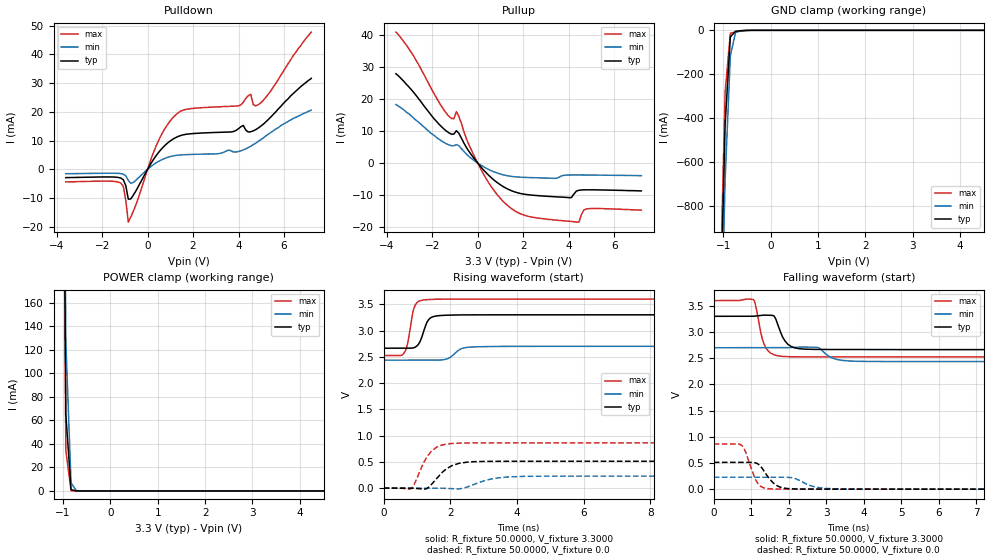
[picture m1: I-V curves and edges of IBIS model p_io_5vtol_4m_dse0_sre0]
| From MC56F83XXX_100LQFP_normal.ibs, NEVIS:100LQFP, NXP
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[Model] p_io_5vtol_4m_dse0_sre0
|   Model p_io_5vtol_4m_dse0_sre0
| Library cells for typ/min/max conditions are connected as defined below:
|  pad - External Pad
|  ipp_do - Core Input
|  ipp_obe - Output Buffer Enable
|  esd_boost - vdd_s_3v
|  esd_bus - vdd_s_3v
|  ipp_ame - vss_s_lv
|  ipp_dse - vss_s_lv
|  ipp_ina40a_5vtol - NC
|  ipp_ina40b_5vtol - NC
|  ipp_ina_5vtol - NC
|  ipp_ina_mux_3v - NC
|  ipp_ind - NC
|  ipp_ind_3v - NC
|  ipp_pue - vss_s_lv
|  ipp_sre - vss_s_lv
|  tie_3v - vdd_s_3v
|  tie_hi - vdd_s_lv
|  vbuf_3v - vdd_s_3v
|  vdd_bulk_lv - vdd_s_lv
|  vdd_s_3v - vdd_s_3v
|  vdd_s_lv - vdd_s_lv
|  vss_bulk - vss_s_3v
|  vss_s_3v - vss_s_3v
|  vss_s_lv - vss_s_lv
| All other pins connected to ground
Model_type I/O
Polarity   Non-Inverting
Enable   Active-High
Vinl =   1.1550V
Vinh =   2.3100V
Vmeas =  1.6500V
Cref =   25.0000pF
Rref =   0.5000k
Vref =   0.0V
C_comp   2.7442pF   2.6088pF   2.9166pF
[Temperature Range]   25.0000   0.1250k   -40.0000
[Voltage Range]   3.3000V   2.7000V   3.6000V
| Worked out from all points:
|   slope of the pulldown table from 0 to 0.495 V, typ, clamps not added: 82.8 ohm
|   slope of the pullup table from 0 to 0.495 V, typ, clamps not added: 127 ohm
|   GND clamp passes 1 mA (typ) near -0.56 V on its own axis
|   POWER clamp passes 1 mA (typ) near -0.82 V on its own axis
|   rising waveform, R_fixture 50.0000, V_fixture 3.3000: 20-80 % time 220ps typ, 318ps min, 177ps max; typ from 2.66 V to 3.3 V
|   rising waveform, R_fixture 50.0000, V_fixture 0.0: 20-80 % time 520ps typ, 708ps min, 427ps max; typ from 0 V to 0.512 V
|   falling waveform, R_fixture 50.0000, V_fixture 3.3000: 20-80 % time 253ps typ, 333ps min, 210ps max; typ from 3.3 V to 2.66 V
|   falling waveform, R_fixture 50.0000, V_fixture 0.0: 20-80 % time 337ps typ, 455ps min, 264ps max; typ from 0.512 V to 0 V
[Pulldown]
|Voltage   I(typ)   I(min)   I(max)
-3.6V     -2.92mA    -1.56mA    -4.41mA
-1.18V    -3.075mA   -1.514mA   -4.85mA
-1.07V    -3.642mA   -1.711mA   -5.917mA
-850mV    -10.41mA   -3.881mA   -18.45mA
360mV     4.579mA    2.156mA    7.833mA
1.13V     10.56mA    4.658mA    18.11mA
1.79V     12.28mA    5.123mA    21mA
3.99V     14.08mA    6.16mA     22.06mA
4.54V     13.07mA    8.03mA     26.11mA
4.65V     13.38mA    8.6mA      22.52mA
4.87V     14.37mA    9.7mA      22.49mA
7.2V      31.7mA     20.6mA     47.8mA
[Pullup]
|Voltage   I(typ)   I(min)   I(max)
-3.6V     27.9mA     18.3mA     40.9mA
-2.81V    22mA       14mA       33.3mA
-1.38V    10.01mA    6.04mA     15.54mA
-1.05V    9.045mA    5.403mA    13.85mA
-940mV    10.12mA    5.768mA    16.08mA
-390mV    3.678mA    2.088mA    5.744mA
270mV     -2.258mA   -1.197mA   -3.638mA
1.48V     -8.613mA   -4.152mA   -14.19mA
4.01V     -10.78mA   -3.728mA   -18.16mA
4.45V     -8.487mA   -3.709mA   -18.45mA
4.78V     -8.342mA   -3.73mA    -14.33mA
7.2V      -8.69mA    -3.91mA    -14.69mA
[GND_clamp]
|Voltage   I(typ)   I(min)   I(max)
-3.6V     -31.15A    -31.13A    -31.21A
-1.07V    -1.387A    -1.641A    -1.238A
-960mV    -429.3mA   -680.2mA   -281.1mA
-850mV    -29.75mA   -116.1mA   -13.24mA
-740mV    -4.234mA   -9.703mA   -7.092mA
-630mV    -1.925mA   -1.63mA    -3.569mA
-410mV    -31.96uA   -64.36uA   -35uA
7.2V      0A         0A         0A
[POWER_clamp]
|Voltage   I(typ)   I(min)   I(max)
-3.6V     31.35A     31.03A     31.61A
-1.05V    682.2mA    740.4mA    662.9mA
-940mV    65.1mA     126.6mA    34.32mA
-830mV    1.105mA    6.829mA    165.4uA
-720mV    15.33uA    281.3uA    694.4nA
-610mV    212.1nA    11.41uA    2.964nA
7.2V      0A         0A         0A
[Ramp]
| variable   typ   min   max
dV/dt_r  0.3070/0.5203n   0.1368/0.7078n   0.5174/0.4265n
dV/dt_f  0.3816/0.2526n   0.1581/0.3329n   0.6454/0.2102n
R_load = 50.0000
[Rising Waveform]
R_fixture= 50.0000
V_fixture= 3.3000
V_fixture_min= 2.7000
V_fixture_max= 3.6000
|time   V(typ)   V(min)   V(max)
0s        2.664V     2.436V     2.524V
610.3ps   2.664V     2.436V     2.569V
714.5ps   2.664V     2.436V     2.741V
910.9ps   2.675V     2.436V     3.431V
1.094ns   2.792V     2.437V     3.568V
1.273ns   3.119V     2.437V     3.588V
1.552ns   3.276V     2.437V     3.596V
2.35ns    3.298V     2.659V     3.599V
2.979ns   3.3V       2.694V     3.599V
20ns      3.3V       2.7V       3.6V
[Rising Waveform]
R_fixture= 50.0000
V_fixture= 0.0
V_fixture_min= 0.0
V_fixture_max= 0.0
|time   V(typ)   V(min)   V(max)
0s        1.096nV    96.66nV    914.3pV
817.3ps   -174.2uV   1.791uV    -11.85mV
1.238ns   -20.09mV   132uV      527.3mV
1.432ns   68.46mV    364.3uV    703.1mV
1.774ns   310.6mV    -2.683mV   823mV
2.042ns   424.3mV    -10.1mV    850.1mV
2.694ns   503.4mV    66.34mV    860.8mV
3.192ns   509.9mV    168.5mV    861.5mV
4.049ns   511.3mV    221.6mV    861.7mV
20ns      511.7mV    228.1mV    862.3mV
[Falling Waveform]
R_fixture= 50.0000
V_fixture= 3.3000
V_fixture_min= 2.7000
V_fixture_max= 3.6000
|time   V(typ)   V(min)   V(max)
0s        3.3V       2.7V       3.6V
1.056ns   3.301V     2.7V       3.62V
1.285ns   3.321V     2.7V       2.894V
1.39ns    3.322V     2.7V       2.695V
1.614ns   3.301V     2.7V       2.565V
1.898ns   2.83V      2.7V       2.531V
2.744ns   2.668V     2.71V      2.525V
3.178ns   2.667V     2.499V     2.525V
3.812ns   2.665V     2.441V     2.525V
20ns      2.664V     2.436V     2.524V
[Falling Waveform]
R_fixture= 50.0000
V_fixture= 0.0
V_fixture_min= 0.0
V_fixture_max= 0.0
|time   V(typ)   V(min)   V(max)
0s        511.8mV    228.1mV    862.4mV
740.7ps   511.8mV    228.1mV    838mV
824.6ps   511.7mV    228.1mV    750.7mV
1.166ns   486.7mV    228.1mV    119mV
1.481ns   202.1mV    228.1mV    6.302mV
1.652ns   81.2mV     228mV      2.01mV
1.911ns   16.02mV    227.7mV    767.9uV
2.752ns   448uV      36.41mV    432.9uV
3.473ns   288.4uV    2.353mV    359uV
20ns      60.38uV    38.43uV    87.29uV
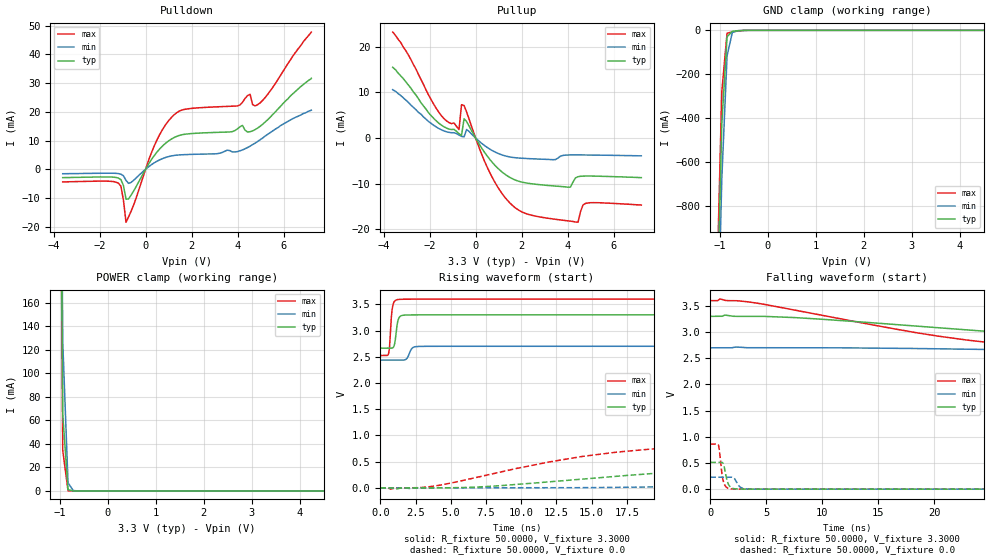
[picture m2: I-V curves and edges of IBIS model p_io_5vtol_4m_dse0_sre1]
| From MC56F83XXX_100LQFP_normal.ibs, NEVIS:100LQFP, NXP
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[Model] p_io_5vtol_4m_dse0_sre1
|   Model p_io_5vtol_4m_dse0_sre1
| Library cells for typ/min/max conditions are connected as defined below:
|  pad - External Pad
|  ipp_do - Core Input
|  ipp_obe - Output Buffer Enable
|  esd_boost - vdd_s_3v
|  esd_bus - vdd_s_3v
|  ipp_ame - vss_s_lv
|  ipp_dse - vss_s_lv
|  ipp_ina40a_5vtol - NC
|  ipp_ina40b_5vtol - NC
|  ipp_ina_5vtol - NC
|  ipp_ina_mux_3v - NC
|  ipp_ind - NC
|  ipp_ind_3v - NC
|  ipp_pue - vss_s_lv
|  ipp_sre - vdd_s_lv
|  tie_3v - vdd_s_3v
|  tie_hi - vdd_s_lv
|  vbuf_3v - vdd_s_3v
|  vdd_bulk_lv - vdd_s_lv
|  vdd_s_3v - vdd_s_3v
|  vdd_s_lv - vdd_s_lv
|  vss_bulk - vss_s_3v
|  vss_s_3v - vss_s_3v
|  vss_s_lv - vss_s_lv
| All other pins connected to ground
Model_type I/O
Polarity   Non-Inverting
Enable   Active-High
Vinl =   1.1550V
Vinh =   2.3100V
Vmeas =  1.6500V
Cref =   25.0000pF
Rref =   0.5000k
Vref =   0.0V
C_comp   2.7442pF   2.6088pF   2.9166pF
[Temperature Range]   25.0000   0.1250k   -40.0000
[Voltage Range]   3.3000V   2.7000V   3.6000V
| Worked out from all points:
|   slope of the pulldown table from 0 to 0.495 V, typ, clamps not added: 82.8 ohm
|   slope of the pullup table from 0 to 0.495 V, typ, clamps not added: 127 ohm
|   GND clamp passes 1 mA (typ) near -0.56 V on its own axis
|   POWER clamp passes 1 mA (typ) near -0.82 V on its own axis
|   rising waveform, R_fixture 50.0000, V_fixture 3.3000: 20-80 % time 192ps typ, 268ps min, 163ps max; typ from 2.66 V to 3.3 V
|   rising waveform, R_fixture 50.0000, V_fixture 0.0: 20-80 % time 17.3ns typ, 32.4ns min, 10.8ns max; typ from 0 V to 0.512 V
|   falling waveform, R_fixture 50.0000, V_fixture 3.3000: 20-80 % time 29.9ns typ, 51ns min, 19.5ns max; typ from 3.3 V to 2.66 V
|   falling waveform, R_fixture 50.0000, V_fixture 0.0: 20-80 % time 342ps typ, 422ps min, 300ps max; typ from 0.512 V to 0 V
[Pulldown]
|Voltage   I(typ)   I(min)   I(max)
-3.6V     -2.92mA    -1.56mA    -4.41mA
-1.18V    -3.075mA   -1.514mA   -4.85mA
-1.07V    -3.642mA   -1.711mA   -5.917mA
-850mV    -10.41mA   -3.881mA   -18.45mA
360mV     4.579mA    2.156mA    7.833mA
1.13V     10.56mA    4.658mA    18.11mA
1.79V     12.28mA    5.123mA    21mA
3.99V     14.08mA    6.16mA     22.06mA
4.54V     13.07mA    8.03mA     26.11mA
4.65V     13.38mA    8.6mA      22.52mA
4.87V     14.37mA    9.7mA      22.49mA
7.2V      31.7mA     20.6mA     47.8mA
[Pullup]
|Voltage   I(typ)   I(min)   I(max)
-3.6V     15.5mA     10.6mA     23.2mA
-1.38V    2.47mA     1.56mA     4.28mA
-720mV    935.3uA    641.5uA    1.84mA
-610mV    580.7uA    348.6uA    7.293mA
-500mV    4.215mA    257.3uA    7.125mA
-390mV    3.605mA    1.85mA     5.718mA
710mV     -5.257mA   -2.715mA   -8.512mA
1.81V     -9.375mA   -4.366mA   -15.61mA
4.12V     -10.77mA   -3.714mA   -18.22mA
4.45V     -8.487mA   -3.709mA   -18.45mA
4.78V     -8.342mA   -3.73mA    -14.33mA
7.2V      -8.69mA    -3.91mA    -14.69mA
[GND_clamp]
|Voltage   I(typ)   I(min)   I(max)
-3.6V     -31.15A    -31.13A    -31.21A
-1.07V    -1.387A    -1.641A    -1.238A
-960mV    -429.3mA   -680.2mA   -281.1mA
-850mV    -29.75mA   -116.1mA   -13.24mA
-740mV    -4.234mA   -9.703mA   -7.092mA
-630mV    -1.925mA   -1.63mA    -3.569mA
-410mV    -31.96uA   -64.36uA   -35uA
7.2V      0A         0A         0A
[POWER_clamp]
|Voltage   I(typ)   I(min)   I(max)
-3.6V     31.35A     31.03A     31.61A
-1.05V    682.2mA    740.4mA    662.9mA
-940mV    65.1mA     126.6mA    34.32mA
-830mV    1.105mA    6.829mA    165.4uA
-720mV    15.33uA    281.3uA    694.4nA
-610mV    212.1nA    11.41uA    2.964nA
7.2V      0A         0A         0A
[Ramp]
| variable   typ   min   max
dV/dt_r  0.3071/17.2926n   0.1369/32.3674n   0.5175/10.7611n
dV/dt_f  0.3817/29.8719n   0.1576/51.0200n   0.6456/19.5314n
R_load = 50.0000
[Rising Waveform]
R_fixture= 50.0000
V_fixture= 3.3000
V_fixture_min= 2.7000
V_fixture_max= 3.6000
|time   V(typ)   V(min)   V(max)
0s        2.664V     2.437V     2.524V
605.3ps   2.664V     2.437V     2.579V
657.9ps   2.664V     2.437V     2.693V
807.7ps   2.664V     2.437V     3.325V
923.6ps   2.679V     2.436V     3.511V
1.276ns   3.209V     2.437V     3.592V
1.646ns   3.293V     2.437V     3.597V
2.341ns   3.298V     2.679V     3.598V
3.739ns   3.299V     2.699V     3.598V
250ns     3.3V       2.7V       3.6V
[Rising Waveform]
R_fixture= 50.0000
V_fixture= 0.0
V_fixture_min= 0.0
V_fixture_max= 0.0
|time   V(typ)   V(min)   V(max)
0s        1.096nV    96.66nV    914.3pV
730.2ps   540.1uV    1.417uV    -25.29mV
3.533ns   -267.8uV   -118.1uV   22.43mV
11.84ns   111.3mV    1.042mV    487mV
16.8ns    222mV      9.094mV    681.3mV
24.08ns   354mV      38.46mV    807.6mV
31.02ns   430.3mV    75.05mV    845.8mV
49.75ns   501.2mV    160.4mV    861.8mV
86.96ns   511.7mV    219.4mV    862.5mV
250ns     511.8mV    228.1mV    862.5mV
[Falling Waveform]
R_fixture= 50.0000
V_fixture= 3.3000
V_fixture_min= 2.7000
V_fixture_max= 3.6000
|time   V(typ)   V(min)   V(max)
0s        3.3V       2.7V       3.6V
896.8ps   3.3V       2.7V       3.63V
3.769ns   3.3V       2.7V       3.565V
18.49ns   3.112V     2.686V     2.984V
25.66ns   2.998V     2.664V     2.78V
33.75ns   2.887V     2.635V     2.66V
43.81ns   2.796V     2.595V     2.594V
65.21ns   2.714V     2.521V     2.543V
96.83ns   2.677V     2.472V     2.527V
250ns     2.664V     2.437V     2.524V
[Falling Waveform]
R_fixture= 50.0000
V_fixture= 0.0
V_fixture_min= 0.0
V_fixture_max= 0.0
|time   V(typ)   V(min)   V(max)
0s        511.8mV    228.1mV    862.4mV
711.3ps   511.8mV    228.1mV    851.3mV
813.8ps   511.8mV    228.1mV    743.1mV
1.045ns   511.3mV    228.1mV    281.6mV
1.18ns    474mV      228.1mV    137.9mV
1.57ns    116.7mV    228mV      19.01mV
2.147ns   7.963mV    204.4mV    2.261mV
2.747ns   1.249mV    29.86mV    1.357mV
3.983ns   641.3uV    486.1uV    1mV
250ns     26.94nV    927.1nV    8.795nV
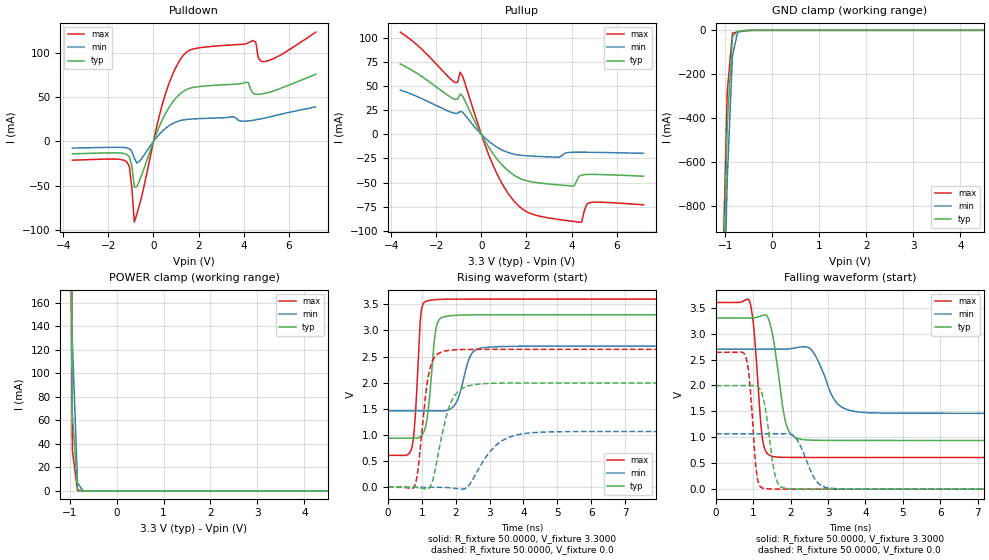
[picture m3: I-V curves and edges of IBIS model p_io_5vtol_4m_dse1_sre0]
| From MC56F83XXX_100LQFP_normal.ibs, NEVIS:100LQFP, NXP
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[Model] p_io_5vtol_4m_dse1_sre0
|   Model p_io_5vtol_4m_dse1_sre0
| Library cells for typ/min/max conditions are connected as defined below:
|  pad - External Pad
|  ipp_do - Core Input
|  ipp_obe - Output Buffer Enable
|  esd_boost - vdd_s_3v
|  esd_bus - vdd_s_3v
|  ipp_ame - vss_s_lv
|  ipp_dse - vdd_s_lv
|  ipp_ina40a_5vtol - NC
|  ipp_ina40b_5vtol - NC
|  ipp_ina_5vtol - NC
|  ipp_ina_mux_3v - NC
|  ipp_ind - NC
|  ipp_ind_3v - NC
|  ipp_pue - vss_s_lv
|  ipp_sre - vss_s_lv
|  tie_3v - vdd_s_3v
|  tie_hi - vdd_s_lv
|  vbuf_3v - vdd_s_3v
|  vdd_bulk_lv - vdd_s_lv
|  vdd_s_3v - vdd_s_3v
|  vdd_s_lv - vdd_s_lv
|  vss_bulk - vss_s_3v
|  vss_s_3v - vss_s_3v
|  vss_s_lv - vss_s_lv
| All other pins connected to ground
Model_type I/O
Polarity   Non-Inverting
Enable   Active-High
Vinl =   1.1550V
Vinh =   2.3100V
Vmeas =  1.6500V
Cref =   25.0000pF
Rref =   0.5000k
Vref =   0.0V
C_comp   2.7442pF   2.6088pF   2.9166pF
[Temperature Range]   25.0000   0.1250k   -40.0000
[Voltage Range]   3.3000V   2.7000V   3.6000V
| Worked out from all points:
|   slope of the pulldown table from 0 to 0.495 V, typ, clamps not added: 16.7 ohm
|   slope of the pullup table from 0 to 0.495 V, typ, clamps not added: 25.7 ohm
|   GND clamp passes 1 mA (typ) near -0.56 V on its own axis
|   POWER clamp passes 1 mA (typ) near -0.82 V on its own axis
|   rising waveform, R_fixture 50.0000, V_fixture 3.3000: 20-80 % time 198ps typ, 316ps min, 148ps max; typ from 0.938 V to 3.3 V
|   rising waveform, R_fixture 50.0000, V_fixture 0.0: 20-80 % time 433ps typ, 731ps min, 266ps max; typ from 0 V to 2 V
|   falling waveform, R_fixture 50.0000, V_fixture 3.3000: 20-80 % time 273ps typ, 438ps min, 181ps max; typ from 3.3 V to 0.939 V
|   falling waveform, R_fixture 50.0000, V_fixture 0.0: 20-80 % time 233ps typ, 387ps min, 161ps max; typ from 2 V to 0 V
[Pulldown]
|Voltage   I(typ)   I(min)   I(max)
-3.6V     -13.95mA   -7.44mA    -21.1mA
-1.18V    -14.7mA    -7.219mA   -23.24mA
-1.07V    -17.36mA   -8.141mA   -28.3mA
-850mV    -51.45mA   -18.95mA   -91.09mA
-630mV    -44.71mA   -22.71mA   -72.44mA
470mV     28.45mA    13.31mA    48.59mA
1.35V     56.89mA    24.4mA     97.86mA
4.1V      66.73mA    22.95mA    110.2mA
4.43V     54.09mA    23.92mA    113.9mA
4.65V     53.15mA    25mA       94.51mA
4.98V     54.48mA    26.7mA     90.35mA
7.2V      75.8mA     39.1mA     123.4mA
[Pullup]
|Voltage   I(typ)   I(min)   I(max)
-3.6V     72.9mA     45.9mA     106mA
-1.16V    36.23mA    21.7mA     53.64mA
-1.05V    36.74mA    21.9mA     54.26mA
-940mV    41.85mA    23.77mA    64.43mA
600mV     -22.66mA   -11.88mA   -36.28mA
1.15V     -36.98mA   -18.56mA   -59.89mA
1.81V     -46.62mA   -21.82mA   -77.16mA
4.12V     -53.36mA   -18.54mA   -90.34mA
4.45V     -42.19mA   -18.52mA   -91.04mA
4.67V     -41.57mA   -18.57mA   -72.57mA
4.78V     -41.5mA    -18.6mA    -70.99mA
7.2V      -43.39mA   -19.66mA   -73.06mA
[GND_clamp]
|Voltage   I(typ)   I(min)   I(max)
-3.6V     -31.15A    -31.13A    -31.21A
-1.07V    -1.387A    -1.641A    -1.238A
-960mV    -429.3mA   -680.2mA   -281.1mA
-850mV    -29.75mA   -116.1mA   -13.24mA
-740mV    -4.234mA   -9.703mA   -7.092mA
-630mV    -1.925mA   -1.63mA    -3.569mA
-410mV    -31.96uA   -64.36uA   -35uA
7.2V      0A         0A         0A
[POWER_clamp]
|Voltage   I(typ)   I(min)   I(max)
-3.6V     31.35A     31.03A     31.61A
-1.05V    682.2mA    740.4mA    662.9mA
-940mV    65.1mA     126.6mA    34.32mA
-830mV    1.105mA    6.829mA    165.4uA
-720mV    15.33uA    281.3uA    694.4nA
-610mV    212.1nA    11.41uA    2.964nA
7.2V      0A         0A         0A
[Ramp]
| variable   typ   min   max
dV/dt_r  1.1975/0.4329n   0.6401/0.7312n   1.5830/0.2663n
dV/dt_f  1.4166/0.2733n   0.7428/0.4382n   1.7935/0.1810n
R_load = 50.0000
[Rising Waveform]
R_fixture= 50.0000
V_fixture= 3.3000
V_fixture_min= 2.7000
V_fixture_max= 3.6000
|time   V(typ)   V(min)   V(max)
0s        938.5mV    1.461V     610.4mV
700.1ps   938.2mV    1.461V     747.1mV
796.4ps   936.7mV    1.461V     1.287V
950.6ps   966.3mV    1.461V     3.178V
1.101ns   1.142V     1.462V     3.551V
1.388ns   2.926V     1.461V     3.588V
1.622ns   3.255V     1.459V     3.595V
1.984ns   3.288V     1.584V     3.598V
2.713ns   3.298V     2.658V     3.599V
10ns      3.3V       2.7V       3.6V
[Rising Waveform]
R_fixture= 50.0000
V_fixture= 0.0
V_fixture_min= 0.0
V_fixture_max= 0.0
|time   V(typ)   V(min)   V(max)
0s        411.9pV    47.82nV    286.1pV
789.5ps   -503.9uV   655.3nV    31.27mV
878.5ps   -6.744mV   -6.775uV   304.7mV
1.188ns   -27.08mV   110.8uV    2.128V
1.538ns   828.6mV    -14.89uV   2.576V
1.891ns   1.669V     -15.27mV   2.625V
2.523ns   1.961V     173.5mV    2.637V
3.139ns   1.99V      774.3mV    2.638V
3.956ns   1.995V     1.021V     2.638V
10ns      1.996V     1.067V     2.638V
[Falling Waveform]
R_fixture= 50.0000
V_fixture= 3.3000
V_fixture_min= 2.7000
V_fixture_max= 3.6000
|time   V(typ)   V(min)   V(max)
0s        3.3V       2.7V       3.6V
897ps     3.3V       2.7V       3.62V
1.012ns   3.302V     2.7V       3.118V
1.248ns   3.352V     2.7V       952.4mV
1.481ns   3.092V     2.7V       637.9mV
1.861ns   1.291V     2.7V       613mV
2.204ns   973.7mV    2.735V     611.7mV
2.551ns   944.9mV    2.689V     611.3mV
3.583ns   939.7mV    1.518V     611mV
10ns      939mV      1.462V     610.8mV
[Falling Waveform]
R_fixture= 50.0000
V_fixture= 0.0
V_fixture_min= 0.0
V_fixture_max= 0.0
|time   V(typ)   V(min)   V(max)
0s        1.996V     1.067V     2.639V
793.2ps   1.996V     1.067V     2.557V
892.4ps   1.996V     1.067V     2.131V
1.088ns   1.992V     1.067V     303.9mV
1.245ns   1.808V     1.067V     21.49mV
1.576ns   285.6mV    1.067V     1.916mV
1.813ns   22.93mV    1.069V     779.9uV
2.113ns   4.177mV    1.006V     534.5uV
2.932ns   535.4uV    34.39mV    380.9uV
10ns      242.2uV    204.3uV    218.8uV
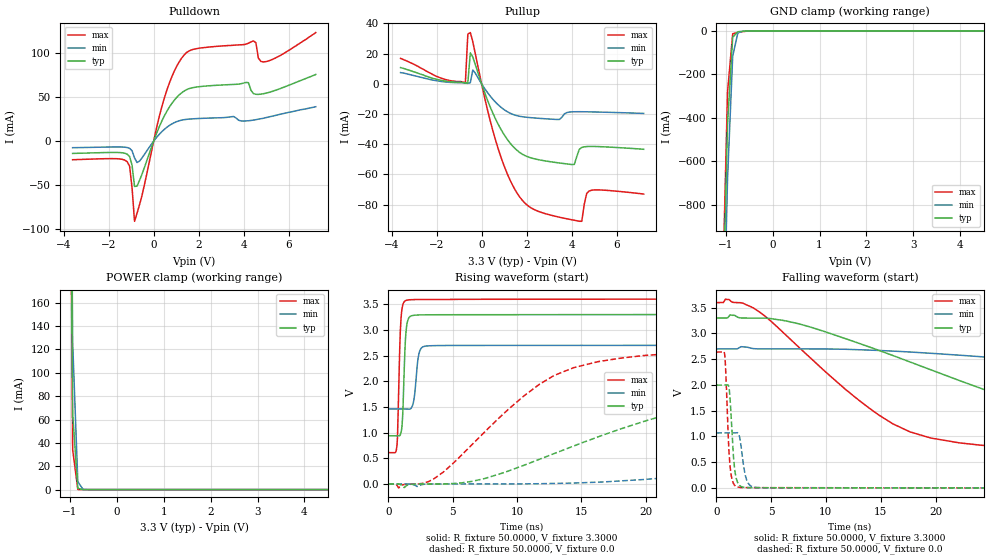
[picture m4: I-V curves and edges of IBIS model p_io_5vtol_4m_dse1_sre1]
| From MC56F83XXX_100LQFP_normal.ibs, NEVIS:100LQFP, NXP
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[Model] p_io_5vtol_4m_dse1_sre1
|   Model p_io_5vtol_4m_dse1_sre1
| Library cells for typ/min/max conditions are connected as defined below:
|  pad - External Pad
|  ipp_do - Core Input
|  ipp_obe - Output Buffer Enable
|  esd_boost - vdd_s_3v
|  esd_bus - vdd_s_3v
|  ipp_ame - vss_s_lv
|  ipp_dse - vdd_s_lv
|  ipp_ina40a_5vtol - NC
|  ipp_ina40b_5vtol - NC
|  ipp_ina_5vtol - NC
|  ipp_ina_mux_3v - NC
|  ipp_ind - NC
|  ipp_ind_3v - NC
|  ipp_pue - vss_s_lv
|  ipp_sre - vdd_s_lv
|  tie_3v - vdd_s_3v
|  tie_hi - vdd_s_lv
|  vbuf_3v - vdd_s_3v
|  vdd_bulk_lv - vdd_s_lv
|  vdd_s_3v - vdd_s_3v
|  vdd_s_lv - vdd_s_lv
|  vss_bulk - vss_s_3v
|  vss_s_3v - vss_s_3v
|  vss_s_lv - vss_s_lv
| All other pins connected to ground
Model_type I/O
Polarity   Non-Inverting
Enable   Active-High
Vinl =   1.1550V
Vinh =   2.3100V
Vmeas =  1.6500V
Cref =   25.0000pF
Rref =   0.5000k
Vref =   0.0V
C_comp   2.7442pF   2.6088pF   2.9166pF
[Temperature Range]   25.0000   0.1250k   -40.0000
[Voltage Range]   3.3000V   2.7000V   3.6000V
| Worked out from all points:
|   slope of the pulldown table from 0 to 0.495 V, typ, clamps not added: 16.7 ohm
|   slope of the pullup table from 0 to 0.495 V, typ, clamps not added: 25.7 ohm
|   GND clamp passes 1 mA (typ) near -0.56 V on its own axis
|   POWER clamp passes 1 mA (typ) near -0.82 V on its own axis
|   rising waveform, R_fixture 50.0000, V_fixture 3.3000: 20-80 % time 204ps typ, 291ps min, 192ps max; typ from 0.938 V to 3.3 V
|   rising waveform, R_fixture 50.0000, V_fixture 0.0: 20-80 % time 15ns typ, 33.8ns min, 7.32ns max; typ from 0 V to 2 V
|   falling waveform, R_fixture 50.0000, V_fixture 3.3000: 20-80 % time 20.3ns typ, 47.8ns min, 10.3ns max; typ from 3.3 V to 0.939 V
|   falling waveform, R_fixture 50.0000, V_fixture 0.0: 20-80 % time 361ps typ, 455ps min, 322ps max; typ from 2 V to 0 V
[Pulldown]
|Voltage   I(typ)   I(min)   I(max)
-3.6V     -13.95mA   -7.44mA    -21.1mA
-1.18V    -14.7mA    -7.219mA   -23.24mA
-1.07V    -17.36mA   -8.141mA   -28.3mA
-850mV    -51.45mA   -18.95mA   -91.09mA
-630mV    -44.71mA   -22.71mA   -72.44mA
470mV     28.45mA    13.31mA    48.59mA
1.35V     56.89mA    24.4mA     97.86mA
4.1V      66.73mA    22.95mA    110.2mA
4.43V     54.09mA    23.92mA    113.9mA
4.65V     53.15mA    25mA       94.51mA
4.98V     54.48mA    26.7mA     90.35mA
7.2V      75.8mA     39.1mA     123.4mA
[Pullup]
|Voltage   I(typ)   I(min)   I(max)
-3.6V     10.7mA     7.4mA      16.8mA
-720mV    464.1uA    412uA      663.7uA
-610mV    644.7uA    224.1uA    32.84mA
-500mV    20.43mA    694.5uA    33.88mA
-390mV    17.73mA    9.113mA    27.82mA
270mV     -11.14mA   -5.959mA   -17.74mA
930mV     -31.96mA   -16.36mA   -51.5mA
2.25V     -49.29mA   -22.53mA   -82.62mA
4.12V     -53.36mA   -18.54mA   -90.34mA
4.45V     -42.19mA   -18.52mA   -91.04mA
4.78V     -41.5mA    -18.6mA    -70.99mA
7.2V      -43.37mA   -19.64mA   -73.01mA
[GND_clamp]
|Voltage   I(typ)   I(min)   I(max)
-3.6V     -31.15A    -31.13A    -31.21A
-1.07V    -1.387A    -1.641A    -1.238A
-960mV    -429.3mA   -680.2mA   -281.1mA
-850mV    -29.75mA   -116.1mA   -13.24mA
-740mV    -4.234mA   -9.703mA   -7.092mA
-630mV    -1.925mA   -1.63mA    -3.569mA
-410mV    -31.96uA   -64.36uA   -35uA
7.2V      0A         0A         0A
[POWER_clamp]
|Voltage   I(typ)   I(min)   I(max)
-3.6V     31.35A     31.03A     31.61A
-1.05V    682.2mA    740.4mA    662.9mA
-940mV    65.1mA     126.6mA    34.32mA
-830mV    1.105mA    6.829mA    165.4uA
-720mV    15.33uA    281.3uA    694.4nA
-610mV    212.1nA    11.41uA    2.964nA
7.2V      0A         0A         0A
[Ramp]
| variable   typ   min   max
dV/dt_r  1.1978/15.0329n   0.6404/33.7874n   1.5836/7.3220n
dV/dt_f  1.4169/20.2724n   0.7410/47.8239n   1.7938/10.2732n
R_load = 50.0000
[Rising Waveform]
R_fixture= 50.0000
V_fixture= 3.3000
V_fixture_min= 2.7000
V_fixture_max= 3.6000
|time   V(typ)   V(min)   V(max)
0s        938.5mV    1.461V     610.4mV
675.5ps   938.3mV    1.461V     767.4mV
892ps     943.3mV    1.461V     2.714V
1.016ns   1.04V      1.462V     3.317V
1.369ns   2.962V     1.46V      3.574V
1.724ns   3.268V     1.464V     3.589V
1.976ns   3.285V     1.625V     3.591V
2.447ns   3.292V     2.597V     3.593V
3.697ns   3.296V     2.695V     3.594V
250ns     3.3V       2.7V       3.6V
[Rising Waveform]
R_fixture= 50.0000
V_fixture= 0.0
V_fixture_min= 0.0
V_fixture_max= 0.0
|time   V(typ)   V(min)   V(max)
0s        411.9pV    47.82nV    286.1pV
809.7ps   -1.184mV   462.7nV    -76.51mV
3.535ns   -1.366mV   -796.3uV   98.92mV
7.51ns    107.1mV    -567.1uV   1.018V
12.9ns    593mV      8.961mV    2.115V
16.32ns   919.5mV    34.89mV    2.384V
24.47ns   1.525V     181.4mV    2.574V
41.82ns   1.922V     584.7mV    2.634V
76.8ns    1.993V     978.9mV    2.639V
250ns     1.996V     1.067V     2.639V
[Falling Waveform]
R_fixture= 50.0000
V_fixture= 3.3000
V_fixture_min= 2.7000
V_fixture_max= 3.6000
|time   V(typ)   V(min)   V(max)
0s        3.3V       2.7V       3.6V
1.145ns   3.331V     2.7V       3.664V
3.719ns   3.3V       2.701V     3.449V
12.6ns    2.84V      2.687V     1.772V
17.68ns   2.447V     2.64V      1.088V
30.07ns   1.542V     2.447V     740mV
47.45ns   1.129V     2.107V     648.6mV
66.29ns   1.018V     1.811V     621.7mV
92.9ns    963.2mV    1.625V     612.6mV
250ns     938.6mV    1.465V     610.4mV
[Falling Waveform]
R_fixture= 50.0000
V_fixture= 0.0
V_fixture_min= 0.0
V_fixture_max= 0.0
|time   V(typ)   V(min)   V(max)
0s        1.996V     1.067V     2.639V
778.8ps   1.996V     1.067V     2.569V
1.153ns   1.953V     1.067V     725.2mV
1.354ns   1.386V     1.067V     249.2mV
1.72ns    295.5mV    1.068V     41.51mV
2.05ns    65.68mV    1.044V     11.5mV
2.32ns    21mV       708.7mV    6.044mV
2.897ns   4.141mV    93.7mV     4.213mV
4.036ns   2.464mV    2.545mV    3.584mV
250ns     28.96nV    453.9nV    -590pV
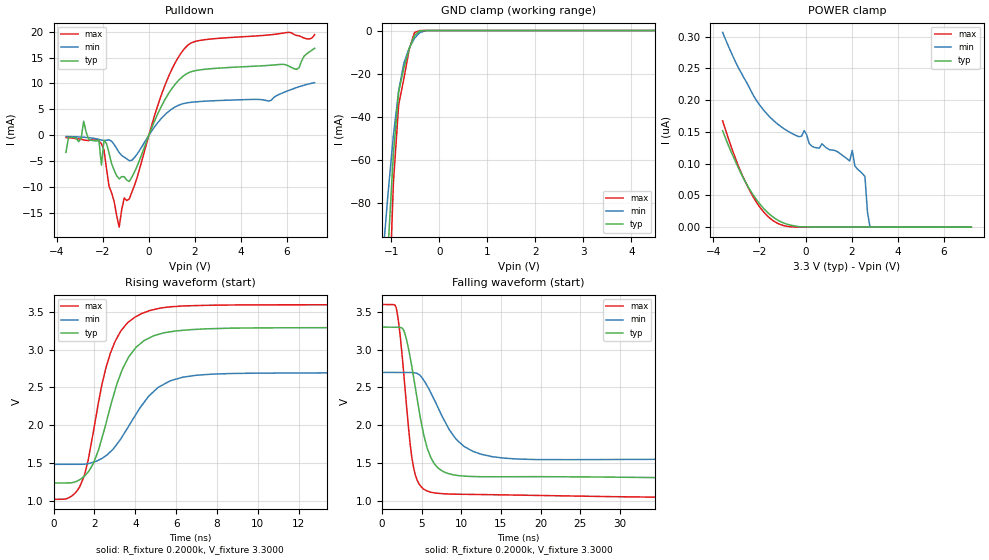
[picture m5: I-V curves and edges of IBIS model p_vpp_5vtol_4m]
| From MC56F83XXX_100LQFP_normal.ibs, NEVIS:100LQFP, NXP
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[Model] p_vpp_5vtol_4m
|   Model p_vpp_5vtol_4m
| Library cells for typ/min/max conditions are connected as defined below:
|  pad_vpp - External Pad
|  ipp_do - Core Input
|  ipp_obe - Output Buffer Enable
|  esd_boost - vdd_s_3v
|  esd_bus - vdd_s_3v
|  ipp_ina_hv - NC
|  ipp_ind - NC
|  ipp_ind_3v - NC
|  tie_3v - vdd_s_3v
|  tie_hi - vdd_s_lv
|  vbuf_3v - vdd_s_3v
|  vdd_bulk_lv - vdd_s_lv
|  vdd_s_3v - vdd_s_3v
|  vdd_s_lv - vdd_s_lv
|  vpp1 - NC
|  vpp2 - NC
|  vss_bulk - vss_s_3v
|  vss_s_3v - vss_s_3v
|  vss_s_lv - vss_s_lv
| All other pins connected to ground
Model_type I/O_open_drain
Polarity   Non-Inverting
Enable   Active-High
Vinl =   1.1550V
Vinh =   2.3100V
Vmeas =  1.6500V
Cref =   25.0000pF
Rref =   0.5000k
Vref =   3.3000V
C_comp   4.5066pF   4.4256pF   4.8680pF
[Temperature Range]   25.0000   0.1250k   -40.0000
[Voltage Range]   3.3000V   2.7000V   3.6000V
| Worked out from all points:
|   slope of the pulldown table from 0 to 0.495 V, typ, clamps not added: 96 ohm
|   GND clamp passes 1 mA (typ) near -0.45 V on its own axis
|   rising waveform, R_fixture 0.2000k, V_fixture 3.3000: 20-80 % time 1.48ns typ, 1.9ns min, 1.28ns max; typ from 1.23 V to 3.3 V
|   falling waveform, R_fixture 0.2000k, V_fixture 3.3000: 20-80 % time 2.29ns typ, 4.16ns min, 1.43ns max; typ from 3.3 V to 1.23 V
[Pulldown]
|Voltage   I(typ)   I(min)   I(max)
-3.6V     -3.3mA     -230uA     -440uA
-2.83V    2.71mA     -370uA     -890uA
-2.17V    -934uA     -795uA     -1.099mA
-2.06V    -5.735mA   -925uA     -1.627mA
-1.95V    -984uA     -1.022mA   -2.809mA
-1.29V    -8.402mA   -3.324mA   -17.74mA
-1.07V    -7.999mA   -4.218mA   -12.1mA
-740mV    -8.101mA   -4.842mA   -10.99mA
690mV     6.816mA    3.929mA    9.547mA
1.68V     11.98mA    6.275mA    17.34mA
6.41V     12.73mA    9.2mA      19.27mA
7.2V      16.79mA    10.16mA    19.42mA
[GND_clamp]
|Voltage   I(typ)   I(min)   I(max)
-3.6V     -21.61A    -22.02A    -21.42A
-1.18V    -150.4mA   -105mA     -217.8mA
-1.07V    -100.8mA   -75.37mA   -140.8mA
-960mV    -57.36mA   -48.79mA   -70.83mA
-850mV    -28.47mA   -27.85mA   -34.48mA
-740mV    -17.26mA   -15.02mA   -22.17mA
-630mV    -8.433mA   -8.144mA   -8.685mA
-520mV    -2.311mA   -3.613mA   -946.2uA
-410mV    -157.7uA   -980.4uA   -11.24uA
-300mV    -4.479uA   -116uA     -99.94nA
-190mV    -111nA     -8.623uA   -738.2pA
7.2V      0A         0A         0A
[POWER_clamp]
|Voltage   I(typ)   I(min)   I(max)
-3.6V     151.8nA    306.6nA    167.3nA
-2.48V    62.79nA    222.4nA    61.37nA
-1.49V    18.16nA    171.2nA    12.4nA
-60mV     598.1pA    152nA      4.369pA
380mV     288.1pA    125.6nA    883.4fA
1.92V     253.1pA    104.1nA    370.1fA
2.03V     246.4pA    120.9nA    322.3fA
2.14V     239.6pA    96.6nA     274.6fA
2.58V     215.7pA    79.68nA    71.63fA
2.69V     198.5pA    23.78nA    5.969fA
2.8V      191.4pA    0A         0A
7.2V      0A         0A         0A
[Ramp]
| variable   typ   min   max
dV/dt_r  0.3851/0.9752n   0.1969/1.4569n   0.5572/0.7683n
dV/dt_f  0.3824/2.5316n   0.1964/4.2007n   0.5564/1.7772n
R_load = 50.0000
[Rising Waveform]
R_fixture= 0.2000k
V_fixture= 3.3000
V_fixture_min= 2.7000
V_fixture_max= 3.6000
|time   V(typ)   V(min)   V(max)
0s        1.234V     1.481V     1.018V
884.9ps   1.237V     1.481V     1.06V
1.503ns   1.324V     1.484V     1.328V
1.953ns   1.496V     1.509V     1.919V
2.565ns   2.022V     1.596V     2.763V
3.284ns   2.681V     1.815V     3.247V
4.042ns   3.034V     2.147V     3.441V
5.117ns   3.203V     2.501V     3.546V
7.2ns     3.274V     2.666V     3.588V
350ns     3.3V       2.7V       3.6V
[Falling Waveform]
R_fixture= 0.2000k
V_fixture= 3.3000
V_fixture_min= 2.7000
V_fixture_max= 3.6000
|time   V(typ)   V(min)   V(max)
0s        3.3V       2.7V       3.6V
1.908ns   3.3V       2.7V       3.503V
2.945ns   3.199V     2.7V       2.458V
3.549ns   2.911V     2.699V     1.764V
4.24ns    2.483V     2.692V     1.332V
5.716ns   1.695V     2.521V     1.128V
7.461ns   1.405V     2.148V     1.093V
11.48ns   1.32V      1.653V     1.082V
19.42ns   1.318V     1.545V     1.069V
350ns     1.234V     1.492V     1.018V
